VERSION 5.7 ;
  NOWIREEXTENSIONATPIN ON ;
  DIVIDERCHAR "/" ;
  BUSBITCHARS "[]" ;
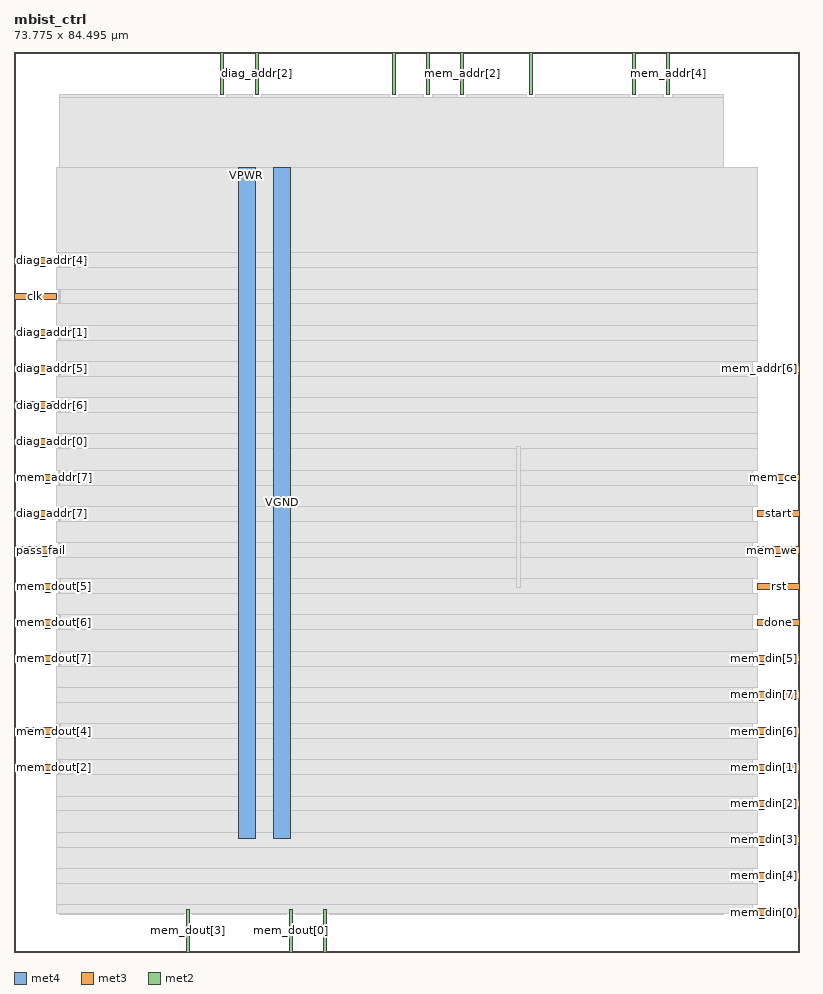
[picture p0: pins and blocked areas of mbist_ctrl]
MACRO mbist_ctrl
  CLASS BLOCK ;
  FOREIGN mbist_ctrl ;
  ORIGIN 0.000 0.000 ;
  SIZE 73.775 BY 84.495 ;
  PIN VGND
    DIRECTION INOUT ;
    USE GROUND ;
    PORT
      LAYER met4 ;
        RECT 24.340 10.640 25.940 73.680 ;
    END
  END VGND
  PIN VPWR
    DIRECTION INOUT ;
    USE POWER ;
    PORT
      LAYER met4 ;
        RECT 21.040 10.640 22.640 73.680 ;
    END
  END VPWR
  PIN clk
    DIRECTION INPUT ;
    USE SIGNAL ;
    ANTENNAGATEAREA 0.852000 ;
    PORT
      LAYER met3 ;
        RECT 0.000 61.240 4.000 61.840 ;
    END
  END clk
  PIN diag_addr[0]
    DIRECTION OUTPUT ;
    USE SIGNAL ;
    ANTENNADIFFAREA 0.445500 ;
    PORT
      LAYER met3 ;
        RECT 0.000 47.640 4.000 48.240 ;
    END
  END diag_addr[0]
  PIN diag_addr[1]
    DIRECTION OUTPUT ;
    USE SIGNAL ;
    ANTENNADIFFAREA 0.445500 ;
    PORT
      LAYER met3 ;
        RECT 0.000 57.840 4.000 58.440 ;
    END
  END diag_addr[1]
  PIN diag_addr[2]
    DIRECTION OUTPUT ;
    USE SIGNAL ;
    ANTENNADIFFAREA 0.445500 ;
    PORT
      LAYER met2 ;
        RECT 22.630 80.495 22.910 84.495 ;
    END
  END diag_addr[2]
  PIN diag_addr[3]
    DIRECTION OUTPUT ;
    USE SIGNAL ;
    ANTENNADIFFAREA 0.445500 ;
    PORT
      LAYER met2 ;
        RECT 19.410 80.495 19.690 84.495 ;
    END
  END diag_addr[3]
  PIN diag_addr[4]
    DIRECTION OUTPUT ;
    USE SIGNAL ;
    ANTENNADIFFAREA 0.445500 ;
    PORT
      LAYER met3 ;
        RECT 0.000 64.640 4.000 65.240 ;
    END
  END diag_addr[4]
  PIN diag_addr[5]
    DIRECTION OUTPUT ;
    USE SIGNAL ;
    ANTENNADIFFAREA 0.445500 ;
    PORT
      LAYER met3 ;
        RECT 0.000 54.440 4.000 55.040 ;
    END
  END diag_addr[5]
  PIN diag_addr[6]
    DIRECTION OUTPUT ;
    USE SIGNAL ;
    ANTENNADIFFAREA 0.445500 ;
    PORT
      LAYER met3 ;
        RECT 0.000 51.040 4.000 51.640 ;
    END
  END diag_addr[6]
  PIN diag_addr[7]
    DIRECTION OUTPUT ;
    USE SIGNAL ;
    ANTENNADIFFAREA 0.445500 ;
    PORT
      LAYER met3 ;
        RECT 0.000 40.840 4.000 41.440 ;
    END
  END diag_addr[7]
  PIN done
    DIRECTION OUTPUT ;
    USE SIGNAL ;
    ANTENNADIFFAREA 0.445500 ;
    PORT
      LAYER met3 ;
        RECT 69.775 30.640 73.775 31.240 ;
    END
  END done
  PIN mem_addr[0]
    DIRECTION OUTPUT ;
    USE SIGNAL ;
    ANTENNADIFFAREA 0.445500 ;
    PORT
      LAYER met2 ;
        RECT 38.730 80.495 39.010 84.495 ;
    END
  END mem_addr[0]
  PIN mem_addr[1]
    DIRECTION OUTPUT ;
    USE SIGNAL ;
    ANTENNADIFFAREA 0.445500 ;
    PORT
      LAYER met2 ;
        RECT 35.510 80.495 35.790 84.495 ;
    END
  END mem_addr[1]
  PIN mem_addr[2]
    DIRECTION OUTPUT ;
    USE SIGNAL ;
    ANTENNADIFFAREA 0.445500 ;
    PORT
      LAYER met2 ;
        RECT 41.950 80.495 42.230 84.495 ;
    END
  END mem_addr[2]
  PIN mem_addr[3]
    DIRECTION OUTPUT ;
    USE SIGNAL ;
    ANTENNADIFFAREA 0.445500 ;
    PORT
      LAYER met2 ;
        RECT 48.390 80.495 48.670 84.495 ;
    END
  END mem_addr[3]
  PIN mem_addr[4]
    DIRECTION OUTPUT ;
    USE SIGNAL ;
    ANTENNADIFFAREA 0.445500 ;
    PORT
      LAYER met2 ;
        RECT 61.270 80.495 61.550 84.495 ;
    END
  END mem_addr[4]
  PIN mem_addr[5]
    DIRECTION OUTPUT ;
    USE SIGNAL ;
    ANTENNADIFFAREA 0.445500 ;
    PORT
      LAYER met2 ;
        RECT 58.050 80.495 58.330 84.495 ;
    END
  END mem_addr[5]
  PIN mem_addr[6]
    DIRECTION OUTPUT ;
    USE SIGNAL ;
    ANTENNADIFFAREA 0.445500 ;
    PORT
      LAYER met3 ;
        RECT 69.775 54.440 73.775 55.040 ;
    END
  END mem_addr[6]
  PIN mem_addr[7]
    DIRECTION OUTPUT ;
    USE SIGNAL ;
    ANTENNADIFFAREA 0.445500 ;
    PORT
      LAYER met3 ;
        RECT 0.000 44.240 4.000 44.840 ;
    END
  END mem_addr[7]
  PIN mem_ce
    DIRECTION OUTPUT ;
    USE SIGNAL ;
    ANTENNADIFFAREA 0.445500 ;
    PORT
      LAYER met3 ;
        RECT 69.775 44.240 73.775 44.840 ;
    END
  END mem_ce
  PIN mem_din[0]
    DIRECTION OUTPUT ;
    USE SIGNAL ;
    ANTENNADIFFAREA 0.445500 ;
    PORT
      LAYER met3 ;
        RECT 69.775 3.440 73.775 4.040 ;
    END
  END mem_din[0]
  PIN mem_din[1]
    DIRECTION OUTPUT ;
    USE SIGNAL ;
    ANTENNADIFFAREA 0.445500 ;
    PORT
      LAYER met3 ;
        RECT 69.775 17.040 73.775 17.640 ;
    END
  END mem_din[1]
  PIN mem_din[2]
    DIRECTION OUTPUT ;
    USE SIGNAL ;
    ANTENNADIFFAREA 0.445500 ;
    PORT
      LAYER met3 ;
        RECT 69.775 13.640 73.775 14.240 ;
    END
  END mem_din[2]
  PIN mem_din[3]
    DIRECTION OUTPUT ;
    USE SIGNAL ;
    ANTENNADIFFAREA 0.445500 ;
    PORT
      LAYER met3 ;
        RECT 69.775 10.240 73.775 10.840 ;
    END
  END mem_din[3]
  PIN mem_din[4]
    DIRECTION OUTPUT ;
    USE SIGNAL ;
    ANTENNADIFFAREA 0.445500 ;
    PORT
      LAYER met3 ;
        RECT 69.775 6.840 73.775 7.440 ;
    END
  END mem_din[4]
  PIN mem_din[5]
    DIRECTION OUTPUT ;
    USE SIGNAL ;
    ANTENNADIFFAREA 0.445500 ;
    PORT
      LAYER met3 ;
        RECT 69.775 27.240 73.775 27.840 ;
    END
  END mem_din[5]
  PIN mem_din[6]
    DIRECTION OUTPUT ;
    USE SIGNAL ;
    ANTENNADIFFAREA 0.445500 ;
    PORT
      LAYER met3 ;
        RECT 69.775 20.440 73.775 21.040 ;
    END
  END mem_din[6]
  PIN mem_din[7]
    DIRECTION OUTPUT ;
    USE SIGNAL ;
    ANTENNADIFFAREA 0.445500 ;
    PORT
      LAYER met3 ;
        RECT 69.775 23.840 73.775 24.440 ;
    END
  END mem_din[7]
  PIN mem_dout[0]
    DIRECTION INPUT ;
    USE SIGNAL ;
    ANTENNAGATEAREA 0.196500 ;
    PORT
      LAYER met2 ;
        RECT 25.850 0.000 26.130 4.000 ;
    END
  END mem_dout[0]
  PIN mem_dout[1]
    DIRECTION INPUT ;
    USE SIGNAL ;
    ANTENNAGATEAREA 0.196500 ;
    PORT
      LAYER met2 ;
        RECT 29.070 0.000 29.350 4.000 ;
    END
  END mem_dout[1]
  PIN mem_dout[2]
    DIRECTION INPUT ;
    USE SIGNAL ;
    ANTENNAGATEAREA 0.196500 ;
    PORT
      LAYER met3 ;
        RECT 0.000 17.040 4.000 17.640 ;
    END
  END mem_dout[2]
  PIN mem_dout[3]
    DIRECTION INPUT ;
    USE SIGNAL ;
    ANTENNAGATEAREA 0.196500 ;
    PORT
      LAYER met2 ;
        RECT 16.190 0.000 16.470 4.000 ;
    END
  END mem_dout[3]
  PIN mem_dout[4]
    DIRECTION INPUT ;
    USE SIGNAL ;
    ANTENNAGATEAREA 0.196500 ;
    PORT
      LAYER met3 ;
        RECT 0.000 20.440 4.000 21.040 ;
    END
  END mem_dout[4]
  PIN mem_dout[5]
    DIRECTION INPUT ;
    USE SIGNAL ;
    ANTENNAGATEAREA 0.196500 ;
    PORT
      LAYER met3 ;
        RECT 0.000 34.040 4.000 34.640 ;
    END
  END mem_dout[5]
  PIN mem_dout[6]
    DIRECTION INPUT ;
    USE SIGNAL ;
    ANTENNAGATEAREA 0.196500 ;
    PORT
      LAYER met3 ;
        RECT 0.000 30.640 4.000 31.240 ;
    END
  END mem_dout[6]
  PIN mem_dout[7]
    DIRECTION INPUT ;
    USE SIGNAL ;
    ANTENNAGATEAREA 0.196500 ;
    PORT
      LAYER met3 ;
        RECT 0.000 27.240 4.000 27.840 ;
    END
  END mem_dout[7]
  PIN mem_we
    DIRECTION OUTPUT ;
    USE SIGNAL ;
    ANTENNADIFFAREA 0.445500 ;
    PORT
      LAYER met3 ;
        RECT 69.775 37.440 73.775 38.040 ;
    END
  END mem_we
  PIN pass_fail
    DIRECTION OUTPUT ;
    USE SIGNAL ;
    ANTENNADIFFAREA 0.445500 ;
    PORT
      LAYER met3 ;
        RECT 0.000 37.440 4.000 38.040 ;
    END
  END pass_fail
  PIN rst
    DIRECTION INPUT ;
    USE SIGNAL ;
    ANTENNAGATEAREA 0.196500 ;
    PORT
      LAYER met3 ;
        RECT 69.775 34.040 73.775 34.640 ;
    END
  END rst
  PIN start
    DIRECTION INPUT ;
    USE SIGNAL ;
    ANTENNAGATEAREA 0.196500 ;
    PORT
      LAYER met3 ;
        RECT 69.775 40.840 73.775 41.440 ;
    END
  END start
  OBS
      LAYER nwell ;
        RECT 5.330 10.795 68.270 73.630 ;
      LAYER li1 ;
        RECT 5.520 10.795 68.080 73.525 ;
      LAYER met1 ;
        RECT 4.210 10.640 68.080 73.680 ;
      LAYER met2 ;
        RECT 4.230 80.215 19.130 80.495 ;
        RECT 19.970 80.215 22.350 80.495 ;
        RECT 23.190 80.215 35.230 80.495 ;
        RECT 36.070 80.215 38.450 80.495 ;
        RECT 39.290 80.215 41.670 80.495 ;
        RECT 42.510 80.215 48.110 80.495 ;
        RECT 48.950 80.215 57.770 80.495 ;
        RECT 58.610 80.215 60.990 80.495 ;
        RECT 61.830 80.215 66.610 80.495 ;
        RECT 4.230 4.280 66.610 80.215 ;
        RECT 4.230 3.555 15.910 4.280 ;
        RECT 16.750 3.555 25.570 4.280 ;
        RECT 26.410 3.555 28.790 4.280 ;
        RECT 29.630 3.555 66.610 4.280 ;
      LAYER met3 ;
        RECT 3.990 65.640 69.775 73.605 ;
        RECT 4.400 64.240 69.775 65.640 ;
        RECT 3.990 62.240 69.775 64.240 ;
        RECT 4.400 60.840 69.775 62.240 ;
        RECT 3.990 58.840 69.775 60.840 ;
        RECT 4.400 57.440 69.775 58.840 ;
        RECT 3.990 55.440 69.775 57.440 ;
        RECT 4.400 54.040 69.375 55.440 ;
        RECT 3.990 52.040 69.775 54.040 ;
        RECT 4.400 50.640 69.775 52.040 ;
        RECT 3.990 48.640 69.775 50.640 ;
        RECT 4.400 47.240 69.775 48.640 ;
        RECT 3.990 45.240 69.775 47.240 ;
        RECT 4.400 43.840 69.375 45.240 ;
        RECT 3.990 41.840 69.775 43.840 ;
        RECT 4.400 40.440 69.375 41.840 ;
        RECT 3.990 38.440 69.775 40.440 ;
        RECT 4.400 37.040 69.375 38.440 ;
        RECT 3.990 35.040 69.775 37.040 ;
        RECT 4.400 33.640 69.375 35.040 ;
        RECT 3.990 31.640 69.775 33.640 ;
        RECT 4.400 30.240 69.375 31.640 ;
        RECT 3.990 28.240 69.775 30.240 ;
        RECT 4.400 26.840 69.375 28.240 ;
        RECT 3.990 24.840 69.775 26.840 ;
        RECT 3.990 23.440 69.375 24.840 ;
        RECT 3.990 21.440 69.775 23.440 ;
        RECT 4.400 20.040 69.375 21.440 ;
        RECT 3.990 18.040 69.775 20.040 ;
        RECT 4.400 16.640 69.375 18.040 ;
        RECT 3.990 14.640 69.775 16.640 ;
        RECT 3.990 13.240 69.375 14.640 ;
        RECT 3.990 11.240 69.775 13.240 ;
        RECT 3.990 9.840 69.375 11.240 ;
        RECT 3.990 7.840 69.775 9.840 ;
        RECT 3.990 6.440 69.375 7.840 ;
        RECT 3.990 4.440 69.775 6.440 ;
        RECT 3.990 3.575 69.375 4.440 ;
      LAYER met4 ;
        RECT 47.215 34.175 47.545 47.425 ;
  END
END mbist_ctrl
END LIBRARY

